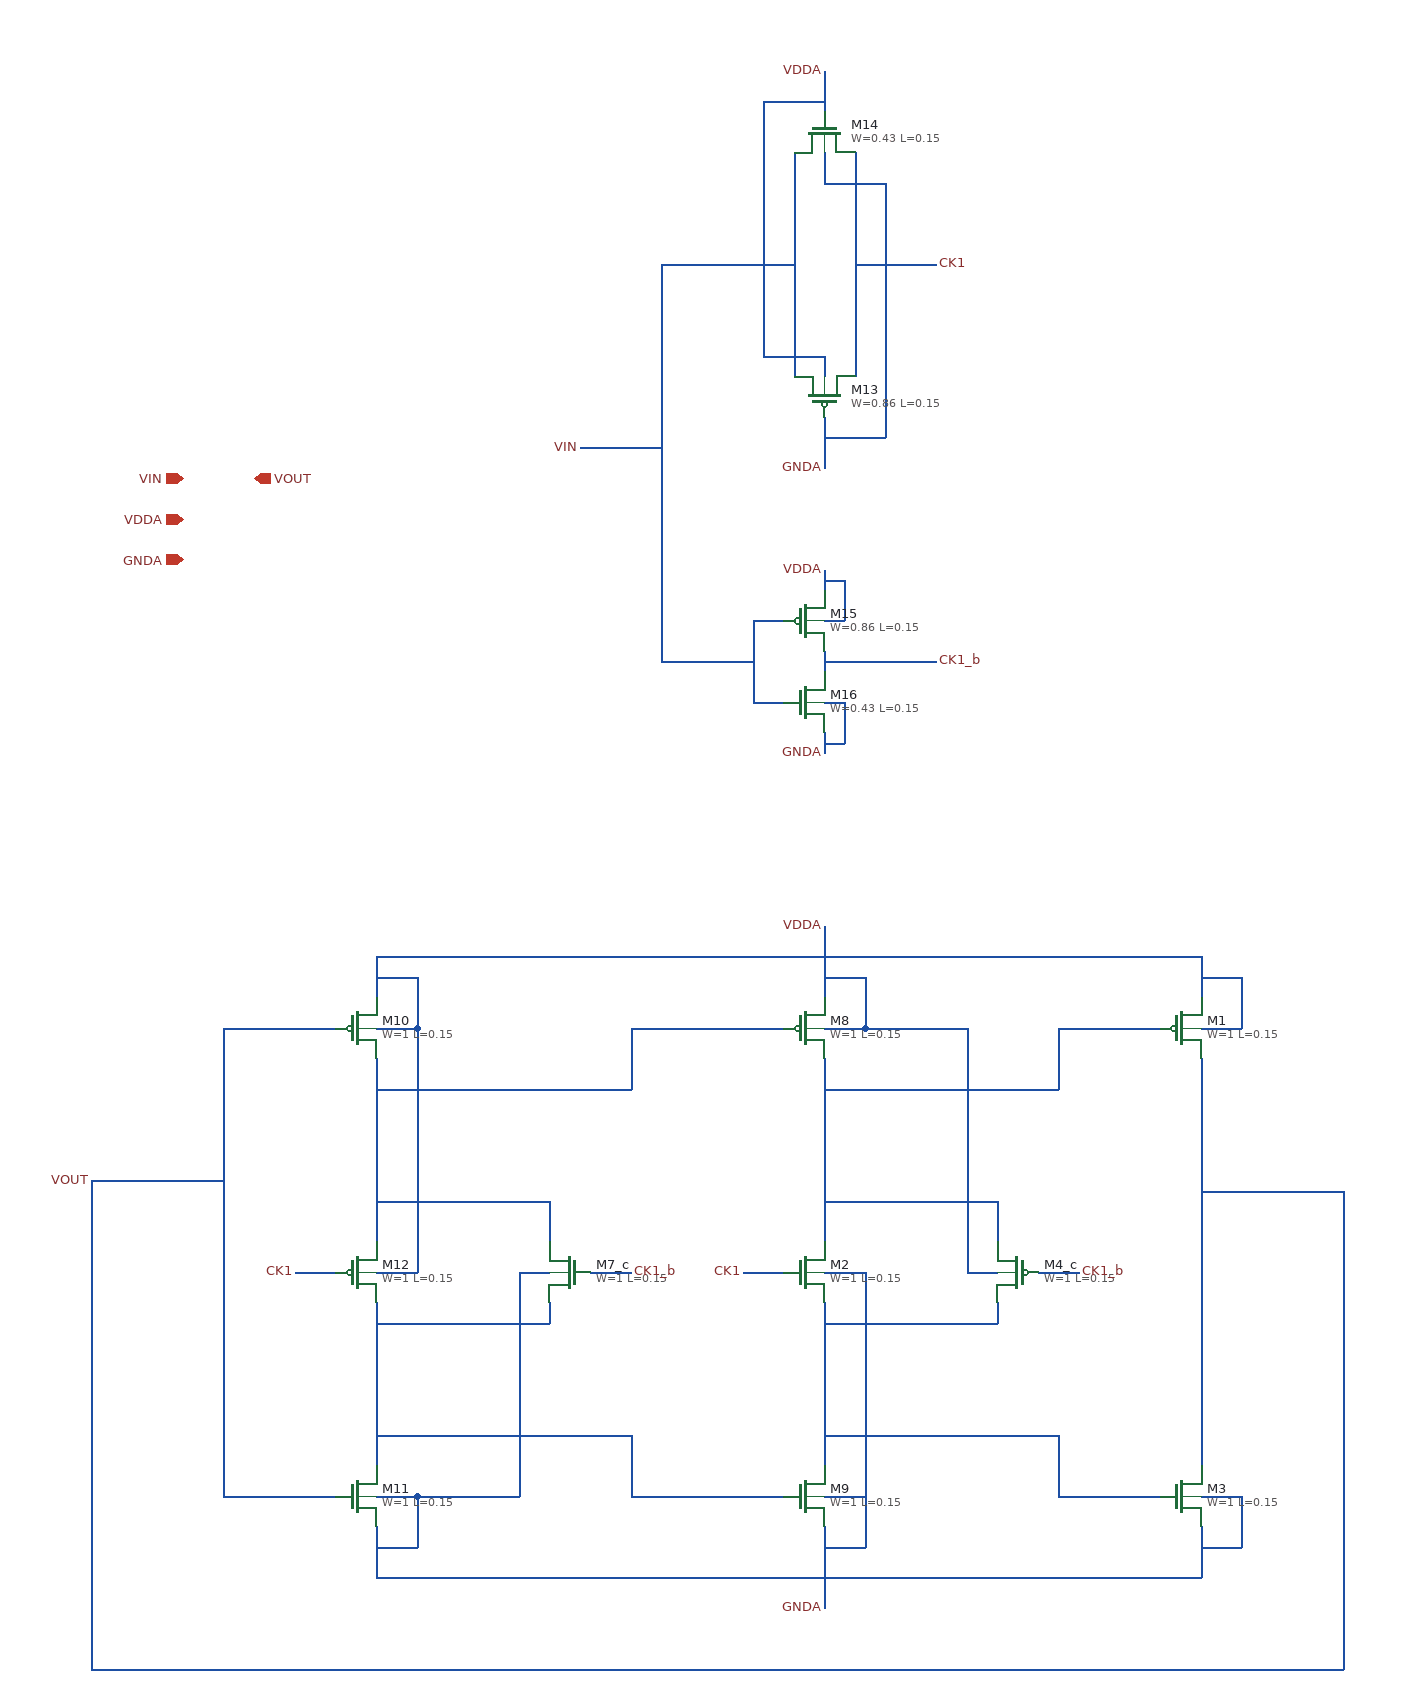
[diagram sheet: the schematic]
v {xschem version=3.4.5 file_version=1.2
}
G {}
K {}
V {}
S {}
E {}
N 1230 -750 1230 -710 {
lab=VDDA}
N 1230 -680 1270 -680 {
lab=VDDA}
N 1270 -730 1270 -680 {
lab=VDDA}
N 1230 -730 1270 -730 {
lab=VDDA}
N 1230 -170 1270 -170 {
lab=GNDA}
N 1230 -190 1230 -140 {
lab=GNDA}
N 1230 -220 1270 -220 {
lab=GNDA}
N 860 -750 860 -710 {
lab=VDDA}
N 860 -680 900 -680 {
lab=VDDA}
N 900 -730 900 -680 {
lab=VDDA}
N 860 -730 900 -730 {
lab=VDDA}
N 860 -440 900 -440 {
lab=GNDA}
N 900 -440 900 -170 {
lab=GNDA}
N 860 -170 900 -170 {
lab=GNDA}
N 860 -190 860 -140 {
lab=GNDA}
N 860 -220 900 -220 {
lab=GNDA}
N 420 -750 420 -710 {
lab=VDDA}
N 420 -680 460 -680 {
lab=VDDA}
N 460 -730 460 -680 {
lab=VDDA}
N 420 -730 460 -730 {
lab=VDDA}
N 420 -440 460 -440 {
lab=VDDA}
N 420 -170 460 -170 {
lab=GNDA}
N 420 -190 420 -140 {
lab=GNDA}
N 420 -220 460 -220 {
lab=GNDA}
N 460 -680 460 -440 {
lab=VDDA}
N 1090 -680 1190 -680 {
lab=#net1}
N 1090 -220 1190 -220 {
lab=#net2}
N 860 -620 1090 -620 {
lab=#net1}
N 270 -680 380 -680 {
lab=VOUT}
N 270 -680 270 -310 {
lab=VOUT}
N 340 -440 380 -440 {
lab=CK1}
N 460 -220 460 -170 {
lab=GNDA}
N 1090 -280 1090 -220 {
lab=#net2}
N 860 -280 1090 -280 {
lab=#net2}
N 670 -220 820 -220 {
lab=#net3}
N 670 -280 670 -220 {
lab=#net3}
N 420 -280 670 -280 {
lab=#net3}
N 670 -680 820 -680 {
lab=#net4}
N 670 -680 670 -620 {
lab=#net4}
N 420 -620 670 -620 {
lab=#net4}
N 1090 -680 1090 -620 {
lab=#net1}
N 1270 -220 1270 -170 {
lab=GNDA}
N 1030 -510 1030 -470 {
lab=#net1}
N 860 -510 1030 -510 {
lab=#net1}
N 1030 -410 1030 -390 {
lab=#net2}
N 860 -390 1030 -390 {
lab=#net2}
N 1000 -440 1030 -440 {
lab=VDDA}
N 1000 -680 1000 -440 {
lab=VDDA}
N 900 -680 1000 -680 {
lab=VDDA}
N 590 -510 590 -470 {
lab=#net4}
N 420 -510 590 -510 {
lab=#net4}
N 590 -410 590 -390 {
lab=#net3}
N 560 -440 590 -440 {
lab=GNDA}
N 420 -390 590 -390 {
lab=#net3}
N 560 -440 560 -220 {
lab=GNDA}
N 460 -220 560 -220 {
lab=GNDA}
N 420 -750 1230 -750 {
lab=VDDA}
N 860 -780 860 -750 {
lab=VDDA}
N 420 -140 1230 -140 {
lab=GNDA}
N 860 -140 860 -110 {
lab=GNDA}
N 630 -440 670 -440 {
lab=CK1_b}
N 1070 -440 1110 -440 {
lab=CK1_b}
N 780 -440 820 -440 {
lab=CK1}
N 140 -530 270 -530 {
lab=VOUT}
N 270 -220 380 -220 {
lab=VOUT}
N 270 -310 270 -220 {
lab=VOUT}
N 1230 -520 1370 -520 {
lab=VOUT}
N 1370 -520 1370 -50 {
lab=VOUT}
N 140 -50 1370 -50 {
lab=VOUT}
N 140 -530 140 -50 {
lab=VOUT}
N 420 -650 420 -470 {
lab=#net4}
N 420 -410 420 -250 {
lab=#net3}
N 860 -650 860 -470 {
lab=#net1}
N 860 -410 860 -250 {
lab=#net2}
N 1230 -650 1230 -250 {
lab=VOUT}
N 830 -1540 830 -1320 {
lab=VIN}
N 890 -1540 890 -1320 {
lab=CK1}
N 860 -1050 860 -1030 {
lab=#net5}
N 790 -1080 820 -1080 {
lab=VIN}
N 790 -1080 790 -1000 {
lab=VIN}
N 790 -1000 820 -1000 {
lab=VIN}
N 860 -970 860 -950 {
lab=GNDA}
N 860 -1000 880 -1000 {
lab=GNDA}
N 880 -1000 880 -960 {
lab=GNDA}
N 860 -960 880 -960 {
lab=GNDA}
N 860 -1130 860 -1110 {
lab=VDDA}
N 860 -1120 880 -1120 {
lab=VDDA}
N 880 -1120 880 -1080 {
lab=VDDA}
N 860 -1080 880 -1080 {
lab=VDDA}
N 860 -1040 970 -1040 {
lab=#net5}
N 620 -1250 700 -1250 {
lab=VIN}
N 890 -1430 970 -1430 {
lab=CK1}
N 860 -1620 860 -1580 {
lab=VDDA}
N 860 -1280 860 -1230 {
lab=GNDA}
N 860 -1540 860 -1510 {
lab=GNDA}
N 860 -1510 920 -1510 {
lab=GNDA}
N 920 -1510 920 -1260 {
lab=GNDA}
N 860 -1260 920 -1260 {
lab=GNDA}
N 860 -1340 860 -1320 {
lab=VDDA}
N 800 -1340 860 -1340 {
lab=VDDA}
N 800 -1590 800 -1340 {
lab=VDDA}
N 800 -1590 860 -1590 {
lab=VDDA}
N 700 -1040 790 -1040 {
lab=VIN}
N 700 -1430 830 -1430 {
lab=VIN}
N 700 -1430 700 -1040 {
lab=VIN}
C {devices/ipin.sym} 230 -1220 0 0 {name=p9 lab=VIN}
C {devices/opin.sym} 300 -1220 0 0 {name=p10 lab=VOUT}
C {devices/ipin.sym} 230 -1180 0 0 {name=p11 lab=VDDA}
C {devices/ipin.sym} 230 -1140 0 0 {name=p12 lab=GNDA}
C {sky130_fd_pr/pfet_01v8.sym} 1210 -680 0 0 {name=M1
L=0.15
W=1
nf=1
mult=1
ad="'int((nf+1)/2) * W/nf * 0.29'" 
pd="'2*int((nf+1)/2) * (W/nf + 0.29)'"
as="'int((nf+2)/2) * W/nf * 0.29'" 
ps="'2*int((nf+2)/2) * (W/nf + 0.29)'"
nrd="'0.29 / W'" nrs="'0.29 / W'"
sa=0 sb=0 sd=0
model=pfet_01v8
spiceprefix=X
}
C {sky130_fd_pr/nfet_01v8.sym} 840 -440 0 0 {name=M2
L=0.15
W=1
nf=1 
mult=1
ad="'int((nf+1)/2) * W/nf * 0.29'" 
pd="'2*int((nf+1)/2) * (W/nf + 0.29)'"
as="'int((nf+2)/2) * W/nf * 0.29'" 
ps="'2*int((nf+2)/2) * (W/nf + 0.29)'"
nrd="'0.29 / W'" nrs="'0.29 / W'"
sa=0 sb=0 sd=0
model=nfet_01v8
spiceprefix=X
}
C {sky130_fd_pr/nfet_01v8.sym} 1210 -220 0 0 {name=M3
L=0.15
W=1
nf=1 
mult=1
ad="'int((nf+1)/2) * W/nf * 0.29'" 
pd="'2*int((nf+1)/2) * (W/nf + 0.29)'"
as="'int((nf+2)/2) * W/nf * 0.29'" 
ps="'2*int((nf+2)/2) * (W/nf + 0.29)'"
nrd="'0.29 / W'" nrs="'0.29 / W'"
sa=0 sb=0 sd=0
model=nfet_01v8
spiceprefix=X
}
C {sky130_fd_pr/pfet_01v8.sym} 840 -680 0 0 {name=M8
L=0.15
W=1
nf=1
mult=1
ad="'int((nf+1)/2) * W/nf * 0.29'" 
pd="'2*int((nf+1)/2) * (W/nf + 0.29)'"
as="'int((nf+2)/2) * W/nf * 0.29'" 
ps="'2*int((nf+2)/2) * (W/nf + 0.29)'"
nrd="'0.29 / W'" nrs="'0.29 / W'"
sa=0 sb=0 sd=0
model=pfet_01v8
spiceprefix=X
}
C {sky130_fd_pr/nfet_01v8.sym} 840 -220 0 0 {name=M9
L=0.15
W=1
nf=1 
mult=1
ad="'int((nf+1)/2) * W/nf * 0.29'" 
pd="'2*int((nf+1)/2) * (W/nf + 0.29)'"
as="'int((nf+2)/2) * W/nf * 0.29'" 
ps="'2*int((nf+2)/2) * (W/nf + 0.29)'"
nrd="'0.29 / W'" nrs="'0.29 / W'"
sa=0 sb=0 sd=0
model=nfet_01v8
spiceprefix=X
}
C {sky130_fd_pr/pfet_01v8.sym} 400 -680 0 0 {name=M10
L=0.15
W=1
nf=1
mult=1
ad="'int((nf+1)/2) * W/nf * 0.29'" 
pd="'2*int((nf+1)/2) * (W/nf + 0.29)'"
as="'int((nf+2)/2) * W/nf * 0.29'" 
ps="'2*int((nf+2)/2) * (W/nf + 0.29)'"
nrd="'0.29 / W'" nrs="'0.29 / W'"
sa=0 sb=0 sd=0
model=pfet_01v8
spiceprefix=X
}
C {sky130_fd_pr/nfet_01v8.sym} 400 -220 0 0 {name=M11
L=0.15
W=1
nf=1 
mult=1
ad="'int((nf+1)/2) * W/nf * 0.29'" 
pd="'2*int((nf+1)/2) * (W/nf + 0.29)'"
as="'int((nf+2)/2) * W/nf * 0.29'" 
ps="'2*int((nf+2)/2) * (W/nf + 0.29)'"
nrd="'0.29 / W'" nrs="'0.29 / W'"
sa=0 sb=0 sd=0
model=nfet_01v8
spiceprefix=X
}
C {sky130_fd_pr/pfet_01v8.sym} 400 -440 0 0 {name=M12
L=0.15
W=1
nf=1
mult=1
ad="'int((nf+1)/2) * W/nf * 0.29'" 
pd="'2*int((nf+1)/2) * (W/nf + 0.29)'"
as="'int((nf+2)/2) * W/nf * 0.29'" 
ps="'2*int((nf+2)/2) * (W/nf + 0.29)'"
nrd="'0.29 / W'" nrs="'0.29 / W'"
sa=0 sb=0 sd=0
model=pfet_01v8
spiceprefix=X
}
C {sky130_fd_pr/pfet_01v8.sym} 1050 -440 0 1 {name=M4_c
L=0.15
W=1
nf=1
mult=1
ad="'int((nf+1)/2) * W/nf * 0.29'" 
pd="'2*int((nf+1)/2) * (W/nf + 0.29)'"
as="'int((nf+2)/2) * W/nf * 0.29'" 
ps="'2*int((nf+2)/2) * (W/nf + 0.29)'"
nrd="'0.29 / W'" nrs="'0.29 / W'"
sa=0 sb=0 sd=0
model=pfet_01v8
spiceprefix=X
}
C {sky130_fd_pr/nfet_01v8.sym} 610 -440 0 1 {name=M7_c
L=0.15
W=1
nf=1 
mult=1
ad="'int((nf+1)/2) * W/nf * 0.29'" 
pd="'2*int((nf+1)/2) * (W/nf + 0.29)'"
as="'int((nf+2)/2) * W/nf * 0.29'" 
ps="'2*int((nf+2)/2) * (W/nf + 0.29)'"
nrd="'0.29 / W'" nrs="'0.29 / W'"
sa=0 sb=0 sd=0
model=nfet_01v8
spiceprefix=X
}
C {devices/lab_pin.sym} 140 -530 0 0 {name=p17 sig_type=std_logic lab=VOUT}
C {devices/lab_pin.sym} 340 -440 0 0 {name=p18 sig_type=std_logic lab=CK1}
C {devices/lab_pin.sym} 780 -440 0 0 {name=p19 sig_type=std_logic lab=CK1}
C {devices/lab_pin.sym} 670 -440 0 1 {name=p20 sig_type=std_logic lab=CK1_b}
C {devices/lab_pin.sym} 1110 -440 0 1 {name=p21 sig_type=std_logic lab=CK1_b}
C {sky130_fd_pr/pfet_01v8.sym} 860 -1300 3 0 {name=M13
L=0.15
W=0.86
nf=2
mult=1
ad="'int((nf+1)/2) * W/nf * 0.29'" 
pd="'2*int((nf+1)/2) * (W/nf + 0.29)'"
as="'int((nf+2)/2) * W/nf * 0.29'" 
ps="'2*int((nf+2)/2) * (W/nf + 0.29)'"
nrd="'0.29 / W'" nrs="'0.29 / W'"
sa=0 sb=0 sd=0
model=pfet_01v8
spiceprefix=X
}
C {sky130_fd_pr/nfet_01v8.sym} 860 -1560 1 0 {name=M14
L=0.15
W=0.43
nf=1 
mult=1
ad="'int((nf+1)/2) * W/nf * 0.29'" 
pd="'2*int((nf+1)/2) * (W/nf + 0.29)'"
as="'int((nf+2)/2) * W/nf * 0.29'" 
ps="'2*int((nf+2)/2) * (W/nf + 0.29)'"
nrd="'0.29 / W'" nrs="'0.29 / W'"
sa=0 sb=0 sd=0
model=nfet_01v8
spiceprefix=X
}
C {sky130_fd_pr/pfet_01v8.sym} 840 -1080 0 0 {name=M15
L=0.15
W=0.86
nf=2
mult=1
ad="'int((nf+1)/2) * W/nf * 0.29'" 
pd="'2*int((nf+1)/2) * (W/nf + 0.29)'"
as="'int((nf+2)/2) * W/nf * 0.29'" 
ps="'2*int((nf+2)/2) * (W/nf + 0.29)'"
nrd="'0.29 / W'" nrs="'0.29 / W'"
sa=0 sb=0 sd=0
model=pfet_01v8
spiceprefix=X
}
C {sky130_fd_pr/nfet_01v8.sym} 840 -1000 0 0 {name=M16
L=0.15
W=0.43
nf=1 
mult=1
ad="'int((nf+1)/2) * W/nf * 0.29'" 
pd="'2*int((nf+1)/2) * (W/nf + 0.29)'"
as="'int((nf+2)/2) * W/nf * 0.29'" 
ps="'2*int((nf+2)/2) * (W/nf + 0.29)'"
nrd="'0.29 / W'" nrs="'0.29 / W'"
sa=0 sb=0 sd=0
model=nfet_01v8
spiceprefix=X
}
C {devices/lab_pin.sym} 970 -1040 0 1 {name=p22 sig_type=std_logic lab=CK1_b}
C {devices/lab_pin.sym} 970 -1430 0 1 {name=p24 sig_type=std_logic lab=CK1}
C {devices/lab_pin.sym} 620 -1250 0 0 {name=p1 sig_type=std_logic lab=VIN}
C {devices/lab_pin.sym} 860 -110 0 0 {name=p2 sig_type=std_logic lab=GNDA}
C {devices/lab_pin.sym} 860 -780 0 0 {name=p3 sig_type=std_logic lab=VDDA}
C {devices/lab_pin.sym} 860 -1130 0 0 {name=p4 sig_type=std_logic lab=VDDA}
C {devices/lab_pin.sym} 860 -950 0 0 {name=p5 sig_type=std_logic lab=GNDA}
C {devices/lab_pin.sym} 860 -1620 0 0 {name=p6 sig_type=std_logic lab=VDDA}
C {devices/lab_pin.sym} 860 -1230 0 0 {name=p7 sig_type=std_logic lab=GNDA}
